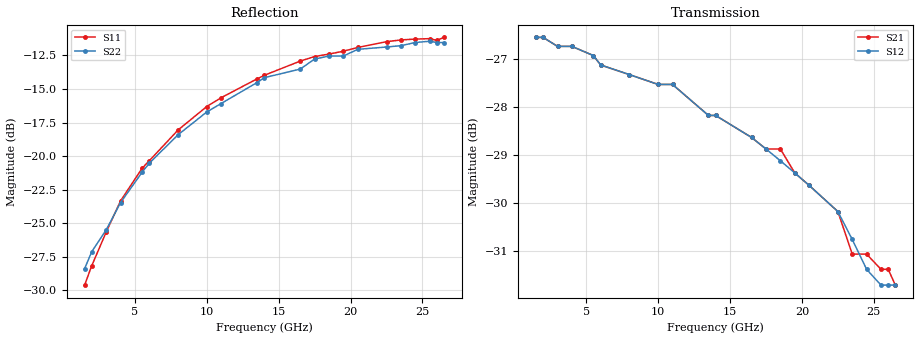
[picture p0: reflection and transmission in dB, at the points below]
! HMMC-1002
! S-PARAMETERS at 27 dB attenuation setting. LAST UPDATED  07-06-99
# GHZ  S  MA  R  50
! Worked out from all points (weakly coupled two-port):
!   51 points, 1.5 GHz to 26.5 GHz, reference 50 ohm
!   highest |S21| = -26.56 dB at 1.5 GHz (marker M1); lowest = -31.7 dB at 26.5 GHz (marker M2)
!   lowest |S11| = -29.6 dB at 1.5 GHz (marker M3), VSWR 1.07, Z = 51.9 - j2.78 ohm
!   |S11| at or under -10 dB: start of sweep to end of sweep
!   |S22| runs from -28.4 to -11.4 dB; largest |S21 - S12| = 0.0011
!   S11 on the Smith chart (normalised r, x): 1.5 GHz: 1.04, -0.06; 8 GHz: 0.84, -0.17; 13.5 GHz: 0.68, -0.06; 18.5 GHz: 0.63, +0.11; 26.5 GHz: 0.74, +0.42
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1.5  0.033 -54.1  0.047 -10.3  0.047 -10.8  0.038 -45.0
2  0.039 -65.1  0.047 -14.6  0.047 -15.1  0.044 -55.3
3  0.052 -80.8  0.046 -21.6  0.046 -21.8  0.053 -73.8
4  0.068 -92.8  0.046 -28.7  0.046 -29.0  0.067 -86.5
5.5  0.09 -108.5  0.045 -38.9  0.045 -39.4  0.087 -104.1
6  0.096 -112.6  0.044 -42.2  0.044 -42.4  0.094 -109.4
8  0.125 -128.7  0.043 -55.3  0.043 -55.6  0.12 -126.9
10  0.153 -143.2  0.042 -68.7  0.042 -68.4  0.146 -142.6
11  0.165 -150.3  0.042 -75.4  0.042 -75.2  0.157 -149.7
13.5  0.194 -167.6  0.039 -92.1  0.039 -92.0  0.188 -169.4
14  0.2 -170.8  0.039 -95.4  0.039 -95.4  0.196 -171.9
16.5  0.226 171.9  0.037 -113.1  0.037 -113.1  0.211 171.0
17.5  0.235 166.0  0.036 -120.5  0.036 -119.9  0.23 164.1
18.5  0.24 159.3  0.036 -126.9  0.035 -127.2  0.236 159.3
19.5  0.246 152.4  0.034 -134.7  0.034 -134.1  0.236 150.9
20.5  0.254 146.4  0.033 -140.4  0.033 -140.7  0.25 143.4
22.5  0.267 133.4  0.031 -155.4  0.031 -155.3  0.255 132.6
23.5  0.271 126.9  0.028 -163.1  0.029 -162.5  0.258 125.6
24.5  0.273 119.5  0.028 -167.4  0.027 -167.4  0.265 117.6
25.5  0.274 112.7  0.027 -172.1  0.026 -172.8  0.268 111.8
26  0.27 110.7  0.027 -175.3  0.026 -174.7  0.265 109.4
26.5  0.277 107.7  0.026 -179.2  0.026 179.6  0.265 107.4
